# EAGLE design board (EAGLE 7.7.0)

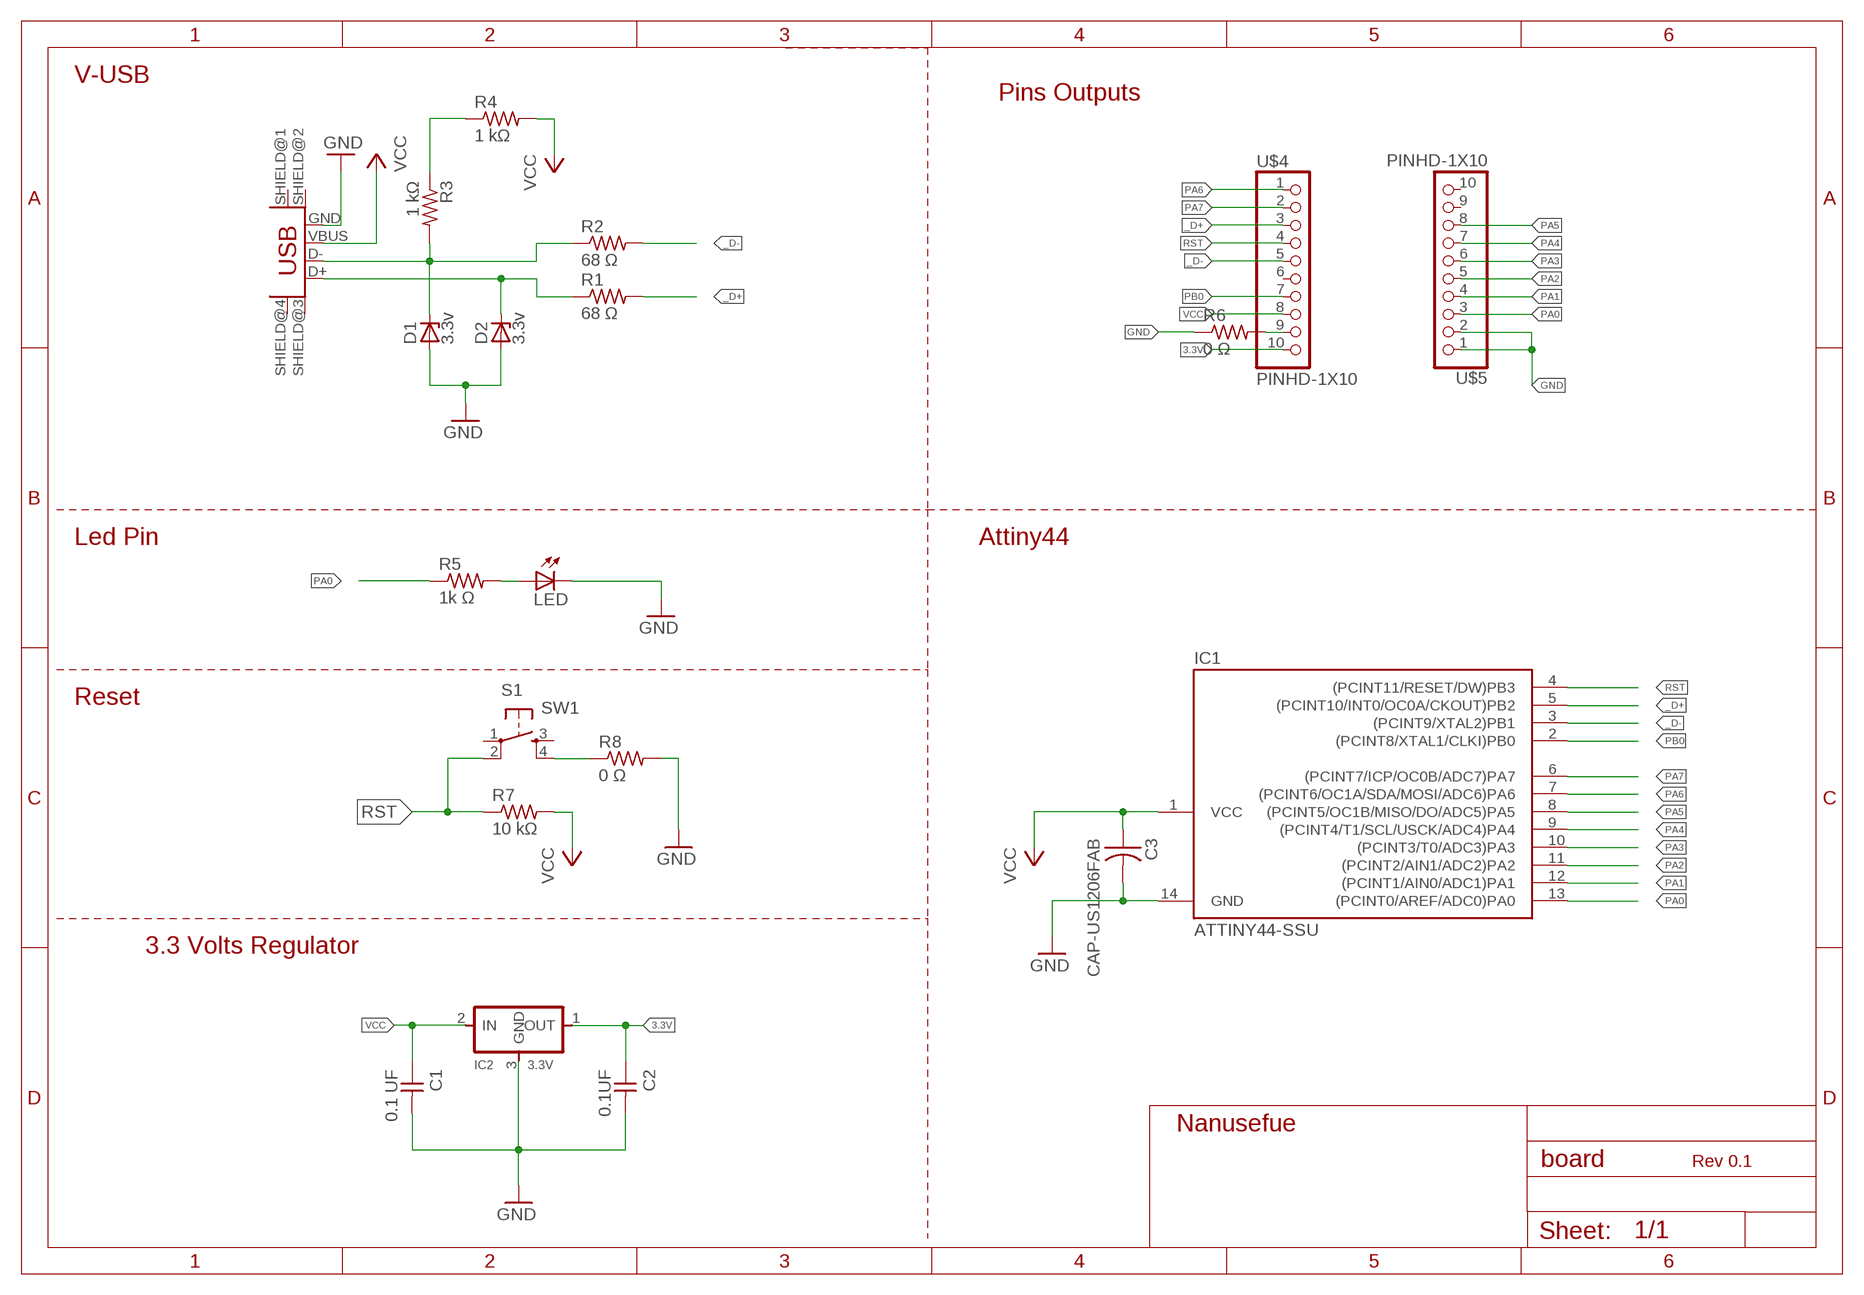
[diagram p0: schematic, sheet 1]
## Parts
C1  0.1 UF  CAP-UNPOLARIZEDFAB  [C1206FAB]
C2  0.1UF  CAP-UNPOLARIZEDFAB  [C1206FAB]
C3  CAP-US1206FAB  [C1206FAB]
D1  3.3v  ZENER_DIODESOD123  [SOD123]
D2  3.3v  ZENER_DIODESOD123  [SOD123]
IC1  ATTINY44-SSU  [SOIC14]
IC2  3.3V  REGULATORSOT23  [SOT23]
LED  LEDFAB1206  [LED1206FAB]
R1  68 Ω  RES-US1206FAB  [R1206FAB]
R2  68 Ω  RES-US1206FAB  [R1206FAB]
R3  1 kΩ  RES-US1206FAB  [R1206FAB]
R4  1 kΩ  RES-US1206FAB  [R1206FAB]
R5  1k Ω  RES-US1206FAB  [R1206FAB]
R6  0 Ω  RES-US1206FAB  [R1206FAB]
R7  10 kΩ  RES-US1206FAB  [R1206FAB]
R8  0 Ω  RES-US1206FAB  [R1206FAB]
S1  SW1  6MM_SWITCH6MM_SWITCH  [6MM_SWITCH]
U$1  USB_MINIB  [USB_MINIB]
U$4  PINHD-1X10  [1X10-BIG]
U$5  PINHD-1X10  [1X10-BIG]

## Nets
3.3V: C2.1 IC2.1(OUT) U$4.10
_D+: IC1.5((PCINT10/INT0/OC0A/CKOUT)PB2) R1.2 U$4.3
_D-: IC1.3((PCINT9/XTAL2)PB1) R2.2 U$4.5
GND: C1.2 C2.2 C3.2 D1.ANODE D2.ANODE IC1.14(GND) IC2.3(GND) LED.2(C) R6.1 R6.2 R8.2 U$1.GND U$4.9 U$5.1 U$5.2
N$1: R8.1 S1.4(S1)
N$2: LED.1(A) R5.2
N$13: R3.1 R4.1
N$17: D2.CATHODE R1.1 U$1.D+
N$18: D1.CATHODE R2.1 R3.2 U$1.D-
PA0: IC1.13((PCINT0/AREF/ADC0)PA0) R5.1 U$5.3
PA1: IC1.12((PCINT1/AIN0/ADC1)PA1) U$5.4
PA2: IC1.11((PCINT2/AIN1/ADC2)PA2) U$5.5
PA3: IC1.10((PCINT3/T0/ADC3)PA3) U$5.6
PA4: IC1.9((PCINT4/T1/SCL/USCK/ADC4)PA4) U$5.7
PA5: IC1.8((PCINT5/OC1B/MISO/DO/ADC5)PA5) U$5.8
PA6: IC1.7((PCINT6/OC1A/SDA/MOSI/ADC6)PA6) U$4.1
PA7: IC1.6((PCINT7/ICP/OC0B/ADC7)PA7) U$4.2
PB0: IC1.2((PCINT8/XTAL1/CLKI)PB0) U$4.7
RST: IC1.4((PCINT11/RESET/DW)PB3) R7.1 S1.2(P1) U$4.4
VCC: C1.1 C3.1 IC1.1(VCC) IC2.2(IN) R4.2 R7.2 U$1.VBUS U$4.8
Unconnected: S1.1(P) S1.3(S) U$1.SHIELD@1(SHIELD) U$1.SHIELD@2(SHIELD1) U$1.SHIELD@3(SHIELD2) U$1.SHIELD@4(SHIELD3) U$4.6 U$5.9 U$5.10

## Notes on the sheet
- V-USB | Pins Outputs
- Attiny44
- Led Pin
- Reset
- 3.3 Volts Regulator
- Nanusefue
- Rev 0.1

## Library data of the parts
C1 C2 = fab_2:CAP-UNPOLARIZED
C3 = fab_2:CAP-US
D1 D2 = fab:ZENER_DIODE: zener diode
IC1 = fab_2:ATTINY44
IC2 = fab_2:REGULATOR
LED = fab_2:LED: LED
R1-R8 = fab:RES-US: Resistor (US Symbol)
S1 = fab:6MM_SWITCH: OMRON SWITCH
U$1 = fab:USB_MINIB
U$4 U$5 = adafruit:PINHD-1X10: Pin header 1x10 0.1" spacing With round pins

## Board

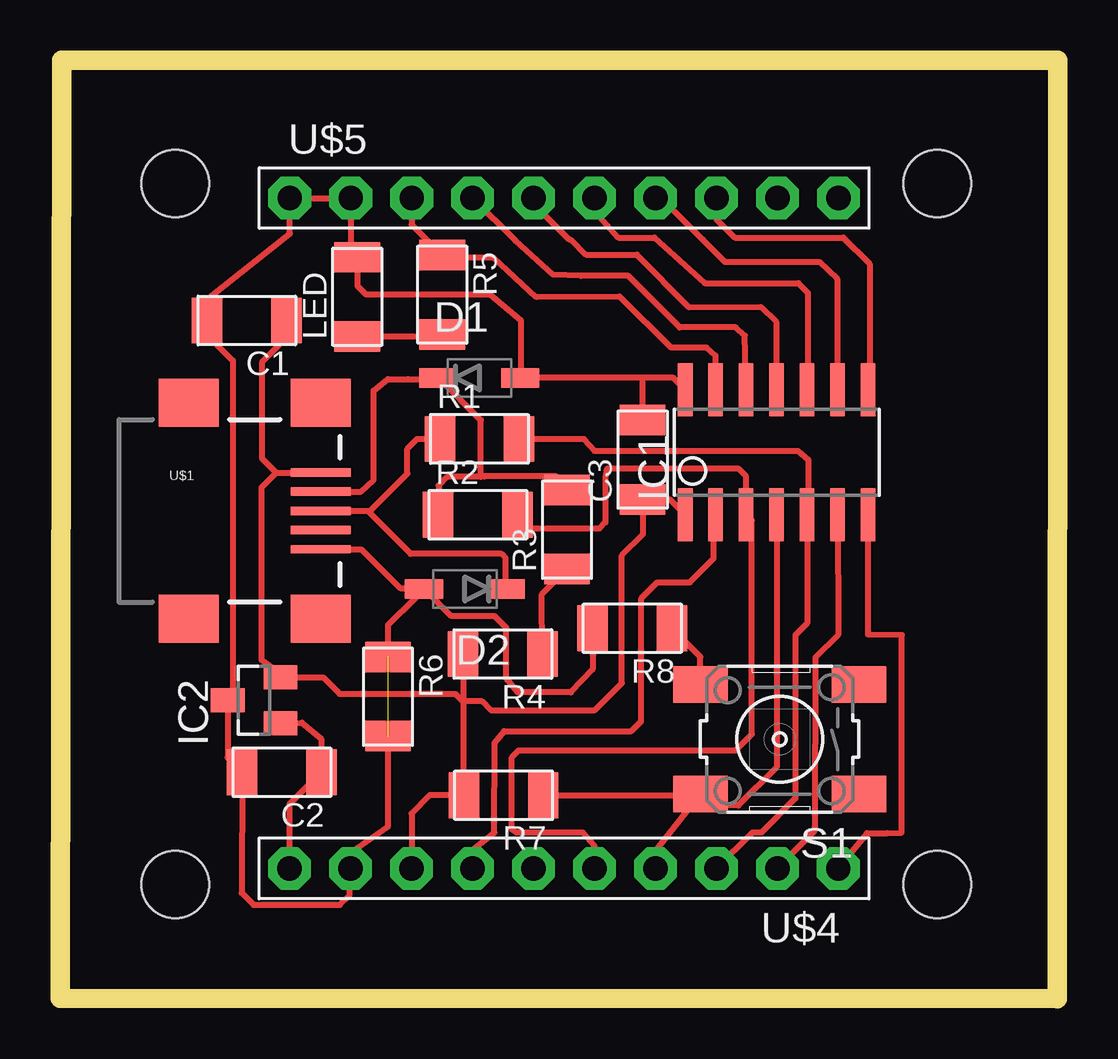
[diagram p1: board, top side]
Size 41.58 x 39.11 mm. Coordinates in mm from the lower left corner, seen from the top.
Outline: 0,0.01 41.56,0 41.58,39.11 0.08,39.11 0,0.01
Copper layers (1*16): Top 0.035mm / dielectric 1.5mm / Bottom 0.035mm
Design rules "fabmodule": minimum track width 10mil, minimum drill 0.4mm, track to track 0.42mm, track to pad 0.42mm, pad to pad 0.42mm, via to via 0.42mm, smd to smd 0.42mm, copper to edge 40mil, drill to drill 0.8mm, minimum pad ring 10mil, minimum via ring 8mil, stop-mask expansion 4mil, vias tented up to drill 0mil, thermal gap 10mil
Holes 2.8 mm at 4.8,33.96 4.8,4.75 36.55,4.75 36.55,33.96

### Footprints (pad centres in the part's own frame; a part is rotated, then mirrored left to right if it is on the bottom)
C1206FAB = smd 1.27 x 1.905: 1 -1.651,0; 2 1.651,0
SOD123 = smd 1.6 x 0.8: ANODE 1.7,0; CATHODE -1.7,0
SOIC14 = smd 0.61 x 2.21: 1 -3.81,-2.603; 2 -2.54,-2.603; 3 -1.27,-2.603; 4 0,-2.603; 5 1.27,-2.603; 6 2.54,-2.603; 7 3.81,-2.603; 8 3.81,2.603; 9 2.54,2.603; 10 1.27,2.603; 11 0,2.603; 12 -1.27,2.603; 13 -2.54,2.603; 14 -3.81,2.603
SOT23 = smd 1 x 1.4: 1 -0.95,-1.1; 2 0.95,-1.1; 3 0,1.1
LED1206FAB = smd 1.27 x 1.905: 1 -1.651,0; 2 1.651,0
R1206FAB = smd 1.27 x 1.905: 1 -1.651,0; 2 1.651,0
6MM_SWITCH = smd 2.286 x 1.524: 1 -3.302,2.286; 2 3.302,2.286; 3 -3.302,-2.286; 4 3.302,-2.286
USB_MINIB = smd 2.5 x 0.35: D+ 3.77,0; D- 3.77,0.8; GND 3.77,-1.6; ID 3.77,-0.8; VBUS 3.77,1.6 | smd 2.5 x 2: SHIELD@1 -1.73,-4.5; SHIELD@2 -1.73,4.5; SHIELD@3 3.77,4.5; SHIELD@4 3.77,-4.5
1X10-BIG = drill 1.016 pad 1.778 octagon: 1 -11.43,0; 2 -8.89,0; 3 -6.35,0; 4 -3.81,0; 5 -1.27,0; 6 1.27,0; 7 3.81,0; 8 6.35,0; 9 8.89,0; 10 11.43,0

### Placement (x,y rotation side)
C1  7.78,28.25 180 top
C2  9.24,9.44 180 top
C3  24.28,22.46 90 top
D1  17.48,25.86 0 top
D2  16.87,17.07 180 top
IC1  29.86,22.76 0 top
IC2  8.09,12.43 90 top
LED  12.39,29.24 90 top
R1  17.48,23.32 0 top
R2  17.41,20.16 0 top
R3  21.12,19.54 90 top
R4  18.45,14.36 180 top
R5  15.92,29.33 270 top
R6  13.67,12.59 270 top
R7  18.48,8.48 180 top
R8  23.84,15.43 180 top
S1  29.99,10.81 180 top
U$1  7.09,20.32 0 top
U$4  21,5.43 180 top
U$5  21,33.36 0 top

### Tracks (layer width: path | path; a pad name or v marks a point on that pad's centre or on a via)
3.3V
  Top 0.26: IC2.1 10.08,11.5 10.88,10.83 C2.1 9.57,8.11 U$4.10
_D+
  Top 0.26: R1.2 21.83,23.32 22.28,22.82 30.75,22.82 31.18,22.44 31.18,20.21 IC1.5 31.13,15.64 30.64,15.15 30.64,8.35 29.22,6.92 28.84,6.92 U$4.3
_D-
  Top 0.26: R2.2 18.94,19.59 22.47,19.59 22.73,19.84 22.73,21.72 22.78,22.07 28.28,22.07 28.59,21.76 IC1.3 28.83,19.92 28.83,11.03 28.15,10.35 19.11,10.35 18.83,10.05 18.83,7.04 19.02,6.92 21.79,6.92 22.27,6.36 U$4.5
GND  (1 unrouted)
  Top 0.26: 19.2,25.89 19.2,28.26 17.91,29.35 12.74,29.35 12.39,29.7 LED.2 12.11,31.17 U$5.2 U$5.1 9.57,31.88 6.13,29.15 C1.2 6,27.79 7.2,26.59 7.2,12.65 IC2.3 6.99,10.04 C2.2 7.57,4.41 8.06,3.91 8.86,3.91 11.66,3.91 12.06,4.31 12.06,5.38 U$4.9 12.1,6.09 13.67,7.18 13.68,9.23 R6.2 | 19.2,25.89 D1.ANODE | 19.2,25.89 24.24,25.89 | 24.24,25.89 25.53,25.89 IC1.14 | C3.2 24.28,25.86 24.24,25.89 | R6.1 13.67,15.57 14.79,16.69 | 14.79,16.69 D2.ANODE 16.31,15.93 18.11,15.93 18.59,15.45 18.59,13.35 19.08,12.76 21.29,12.76 22.19,13.72 R8.2 | U$1.GND 12.55,18.72 14.17,17.1 14.38,17.1 14.79,16.69
N$1
  Top 0.26: S1.4 26.69,14.24 R8.1
N$2
  Top 0.26: LED.1 15.83,27.59 R5.2
N$3  (via drill 0.1 pad 0.25)
  other vias: 4.8,33.96
N$4  (via drill 0.1 pad 0.25)
  other vias: 36.55,33.96
N$5  (via drill 0.1 pad 0.25)
  other vias: 4.8,4.75
N$6  (via drill 0.1 pad 0.25)
  other vias: 36.55,4.75
N$13
  Top 0.26: 21.51,18.37 R3.1 20.08,16.85 R4.1
N$17
  Top 0.26: U$1.D+ 12.82,20.32 | 12.82,20.32 12.95,20.31 12.95,20.35 14.47,21.87 14.47,22.91 14.88,23.33 R1.1 | D2.CATHODE 18.57,18.36 18.4,18.53 14.61,18.53 12.82,20.32
N$18
  Top 0.26: U$1.D- 12.54,21.13 13.07,21.6 13.07,22.92 13.07,25.34 13.67,25.82 14.51,25.81 15.73,25.81 D1.CATHODE 17.54,24.1 17.54,21.74 | 15.94,19.96 R2.1 15.77,20.17 15.77,21.38 16.14,21.74 17.54,21.74 | R3.2 20.9,21.45 20.67,21.76 17.69,21.76 17.54,21.74
PA0
  Top 0.26: U$5.3 14.65,32.25 R5.1 | 15.99,31.05 R5.1 | IC1.13 27.32,26.79 26.95,27.12 25.47,27.12 23.31,29.25 19.85,29.23 18.07,30.87 16.04,30.87 R5.1
PA1
  Top 0.26: IC1.12 28.54,27.62 28.16,27.97 25.81,27.97 23.67,30.11 21.7,30.11 20.54,30.17 18.98,31.57 U$5.4
PA2
  Top 0.26: U$5.5 19.48,33.36 21.2,31.64 21.3,31.62 21.91,31 24.04,31 26.19,28.81 29.19,28.82 29.83,28.21 29.83,25.39 IC1.11
PA3
  Top 0.26: U$5.6 22.27,32.8 23.26,31.71 24.76,31.71 26.86,29.81 30.76,29.81 31.16,29.41 31.16,25.4 IC1.10
PA4
  Top 0.26: U$5.7 25.05,33.36 26.78,31.62 27.18,31.22 27.7,30.7 31.63,30.7 32.38,29.99 32.38,25.39 IC1.9
PA5
  Top 0.26: U$5.8 27.35,32.47 28.12,31.71 32.64,31.71 33.73,30.61 33.73,25.43 IC1.8
PA6
  Top 0.26: U$4.1 33.63,6.89 34.47,6.89 35.07,6.92 35.08,15.15 33.67,15.16 33.67,18.88 IC1.7
PA7
  Top 0.26: IC1.6 32.43,15.16 31.47,14.22 31.45,6.99 U$4.2
PB0
  Top 0.26: U$4.7 17.19,6.19 18.1,6.92 18.11,10.66 18.5,11.15 23.81,11.15 24.21,11.57 24.22,16.67 24.89,17.35 26.24,17.35 27.24,18.34 27.24,20.08 IC1.2
RST
  Top 0.26: IC1.4 29.86,9.65 28.27,8.06 26.72,8.06 S1.2 | R7.1 26.23,8.48 S1.2 | U$4.4 24.81,6.14 S1.2
VCC
  Top 0.26: C1.1 9.27,27.37 8.41,26.51 8.41,22.51 9.01,21.91 | 9.01,21.91 10.85,21.91 U$1.VBUS | 9.01,21.91 8.4,21.3 8.4,14.11 9.19,13.53 IC2.2 10.96,13.38 11.65,12.7 16.47,12.7 16.8,12.36 | IC1.1 25.4,20.81 C3.1 24.3,20.79 24.3,19.36 23.41,18.47 23.41,13.15 22.29,12.02 17.95,12.02 17.59,12.39 16.82,12.39 16.8,12.36 | R4.2 16.8,12.36 | 16.8,12.36 16.8,8.51 R7.2 15.41,8.48 14.65,7.71 U$4.8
